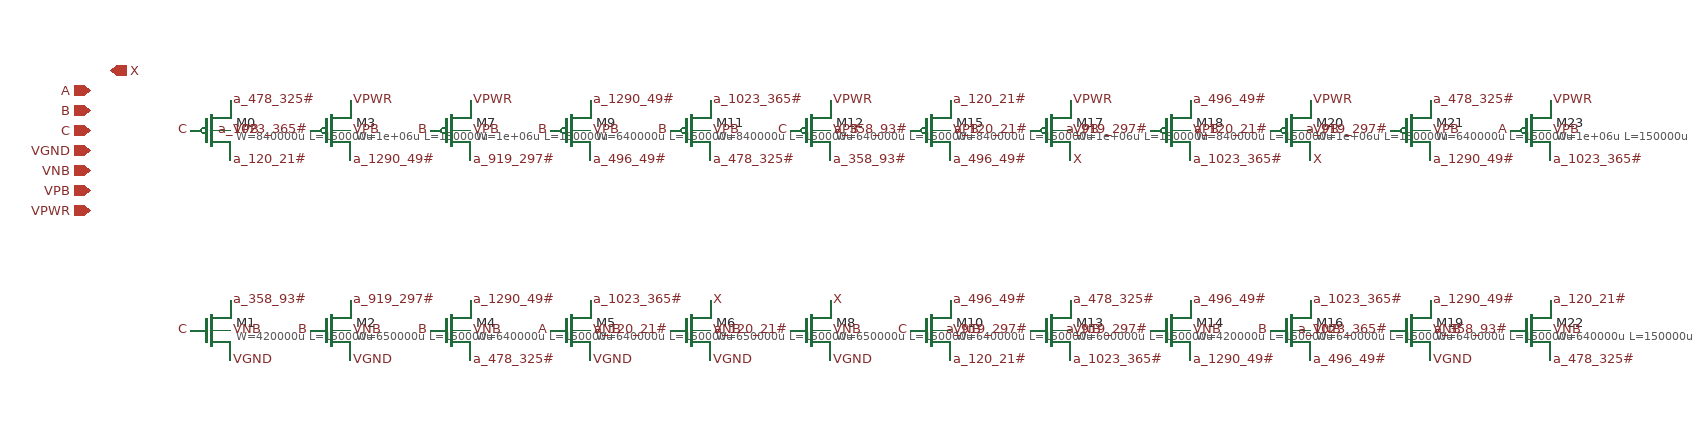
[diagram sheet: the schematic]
v {xschem version=3.4.6RC file_version=1.2
}
G {}
K {}
V {}
S {}
E {}
C {ipin.sym} -120 -40 0 0 {name=p0 lab=A}
C {ipin.sym} -120 -20 0 0 {name=p1 lab=B}
C {ipin.sym} -120 0 0 0 {name=p2 lab=C}
C {ipin.sym} -120 20 0 0 {name=p3 lab=VGND}
C {ipin.sym} -120 40 0 0 {name=p4 lab=VNB}
C {ipin.sym} -120 60 0 0 {name=p5 lab=VPB}
C {ipin.sym} -120 80 0 0 {name=p6 lab=VPWR}
C {opin.sym} -100 -60 0 0 {name=p7 lab=X}
C {sky130_fd_pr/pfet_01v8_hvt.sym} 0 0 0 0 {name=M0
W=840000u
L=150000u
model=pfet_01v8_hvt
spiceprefix=X
}
C {lab_pin.sym} 20 0 2 0 {name=p8 sig_type=std_logic lab=VPB}
C {lab_pin.sym} 20 -30 2 0 {name=p9 sig_type=std_logic lab=a_478_325#}
C {lab_pin.sym} 20 30 2 0 {name=p10 sig_type=std_logic lab=a_120_21#}
C {lab_pin.sym} -20 0 0 0 {name=p11 sig_type=std_logic lab=C}
C {sky130_fd_pr/pfet_01v8_hvt.sym} 120 0 0 0 {name=M3
W=1e+06u
L=150000u
model=pfet_01v8_hvt
spiceprefix=X
}
C {lab_pin.sym} 140 0 2 0 {name=p12 sig_type=std_logic lab=VPB}
C {lab_pin.sym} 140 -30 2 0 {name=p13 sig_type=std_logic lab=VPWR}
C {lab_pin.sym} 140 30 2 0 {name=p14 sig_type=std_logic lab=a_1290_49#}
C {lab_pin.sym} 100 0 0 0 {name=p15 sig_type=std_logic lab=a_1023_365#}
C {sky130_fd_pr/pfet_01v8_hvt.sym} 240 0 0 0 {name=M7
W=1e+06u
L=150000u
model=pfet_01v8_hvt
spiceprefix=X
}
C {lab_pin.sym} 260 0 2 0 {name=p16 sig_type=std_logic lab=VPB}
C {lab_pin.sym} 260 -30 2 0 {name=p17 sig_type=std_logic lab=VPWR}
C {lab_pin.sym} 260 30 2 0 {name=p18 sig_type=std_logic lab=a_919_297#}
C {lab_pin.sym} 220 0 0 0 {name=p19 sig_type=std_logic lab=B}
C {sky130_fd_pr/pfet_01v8_hvt.sym} 360 0 0 0 {name=M9
W=640000u
L=150000u
model=pfet_01v8_hvt
spiceprefix=X
}
C {lab_pin.sym} 380 0 2 0 {name=p20 sig_type=std_logic lab=VPB}
C {lab_pin.sym} 380 -30 2 0 {name=p21 sig_type=std_logic lab=a_1290_49#}
C {lab_pin.sym} 380 30 2 0 {name=p22 sig_type=std_logic lab=a_496_49#}
C {lab_pin.sym} 340 0 0 0 {name=p23 sig_type=std_logic lab=B}
C {sky130_fd_pr/pfet_01v8_hvt.sym} 480 0 0 0 {name=M11
W=840000u
L=150000u
model=pfet_01v8_hvt
spiceprefix=X
}
C {lab_pin.sym} 500 0 2 0 {name=p24 sig_type=std_logic lab=VPB}
C {lab_pin.sym} 500 -30 2 0 {name=p25 sig_type=std_logic lab=a_1023_365#}
C {lab_pin.sym} 500 30 2 0 {name=p26 sig_type=std_logic lab=a_478_325#}
C {lab_pin.sym} 460 0 0 0 {name=p27 sig_type=std_logic lab=B}
C {sky130_fd_pr/pfet_01v8_hvt.sym} 600 0 0 0 {name=M12
W=640000u
L=150000u
model=pfet_01v8_hvt
spiceprefix=X
}
C {lab_pin.sym} 620 0 2 0 {name=p28 sig_type=std_logic lab=VPB}
C {lab_pin.sym} 620 -30 2 0 {name=p29 sig_type=std_logic lab=VPWR}
C {lab_pin.sym} 620 30 2 0 {name=p30 sig_type=std_logic lab=a_358_93#}
C {lab_pin.sym} 580 0 0 0 {name=p31 sig_type=std_logic lab=C}
C {sky130_fd_pr/pfet_01v8_hvt.sym} 720 0 0 0 {name=M15
W=840000u
L=150000u
model=pfet_01v8_hvt
spiceprefix=X
}
C {lab_pin.sym} 740 0 2 0 {name=p32 sig_type=std_logic lab=VPB}
C {lab_pin.sym} 740 -30 2 0 {name=p33 sig_type=std_logic lab=a_120_21#}
C {lab_pin.sym} 740 30 2 0 {name=p34 sig_type=std_logic lab=a_496_49#}
C {lab_pin.sym} 700 0 0 0 {name=p35 sig_type=std_logic lab=a_358_93#}
C {sky130_fd_pr/pfet_01v8_hvt.sym} 840 0 0 0 {name=M17
W=1e+06u
L=150000u
model=pfet_01v8_hvt
spiceprefix=X
}
C {lab_pin.sym} 860 0 2 0 {name=p36 sig_type=std_logic lab=VPB}
C {lab_pin.sym} 860 -30 2 0 {name=p37 sig_type=std_logic lab=VPWR}
C {lab_pin.sym} 860 30 2 0 {name=p38 sig_type=std_logic lab=X}
C {lab_pin.sym} 820 0 0 0 {name=p39 sig_type=std_logic lab=a_120_21#}
C {sky130_fd_pr/pfet_01v8_hvt.sym} 960 0 0 0 {name=M18
W=840000u
L=150000u
model=pfet_01v8_hvt
spiceprefix=X
}
C {lab_pin.sym} 980 0 2 0 {name=p40 sig_type=std_logic lab=VPB}
C {lab_pin.sym} 980 -30 2 0 {name=p41 sig_type=std_logic lab=a_496_49#}
C {lab_pin.sym} 980 30 2 0 {name=p42 sig_type=std_logic lab=a_1023_365#}
C {lab_pin.sym} 940 0 0 0 {name=p43 sig_type=std_logic lab=a_919_297#}
C {sky130_fd_pr/pfet_01v8_hvt.sym} 1080 0 0 0 {name=M20
W=1e+06u
L=150000u
model=pfet_01v8_hvt
spiceprefix=X
}
C {lab_pin.sym} 1100 0 2 0 {name=p44 sig_type=std_logic lab=VPB}
C {lab_pin.sym} 1100 -30 2 0 {name=p45 sig_type=std_logic lab=VPWR}
C {lab_pin.sym} 1100 30 2 0 {name=p46 sig_type=std_logic lab=X}
C {lab_pin.sym} 1060 0 0 0 {name=p47 sig_type=std_logic lab=a_120_21#}
C {sky130_fd_pr/pfet_01v8_hvt.sym} 1200 0 0 0 {name=M21
W=640000u
L=150000u
model=pfet_01v8_hvt
spiceprefix=X
}
C {lab_pin.sym} 1220 0 2 0 {name=p48 sig_type=std_logic lab=VPB}
C {lab_pin.sym} 1220 -30 2 0 {name=p49 sig_type=std_logic lab=a_478_325#}
C {lab_pin.sym} 1220 30 2 0 {name=p50 sig_type=std_logic lab=a_1290_49#}
C {lab_pin.sym} 1180 0 0 0 {name=p51 sig_type=std_logic lab=a_919_297#}
C {sky130_fd_pr/pfet_01v8_hvt.sym} 1320 0 0 0 {name=M23
W=1e+06u
L=150000u
model=pfet_01v8_hvt
spiceprefix=X
}
C {lab_pin.sym} 1340 0 2 0 {name=p52 sig_type=std_logic lab=VPB}
C {lab_pin.sym} 1340 -30 2 0 {name=p53 sig_type=std_logic lab=VPWR}
C {lab_pin.sym} 1340 30 2 0 {name=p54 sig_type=std_logic lab=a_1023_365#}
C {lab_pin.sym} 1300 0 0 0 {name=p55 sig_type=std_logic lab=A}
C {sky130_fd_pr/nfet_01v8.sym} 0 200 0 0 {name=M1
W=420000u
L=150000u
model=nfet_01v8
spiceprefix=X
}
C {lab_pin.sym} 20 200 2 0 {name=p56 sig_type=std_logic lab=VNB}
C {lab_pin.sym} 20 170 2 0 {name=p57 sig_type=std_logic lab=a_358_93#}
C {lab_pin.sym} 20 230 2 0 {name=p58 sig_type=std_logic lab=VGND}
C {lab_pin.sym} -20 200 0 0 {name=p59 sig_type=std_logic lab=C}
C {sky130_fd_pr/nfet_01v8.sym} 120 200 0 0 {name=M2
W=650000u
L=150000u
model=nfet_01v8
spiceprefix=X
}
C {lab_pin.sym} 140 200 2 0 {name=p60 sig_type=std_logic lab=VNB}
C {lab_pin.sym} 140 170 2 0 {name=p61 sig_type=std_logic lab=a_919_297#}
C {lab_pin.sym} 140 230 2 0 {name=p62 sig_type=std_logic lab=VGND}
C {lab_pin.sym} 100 200 0 0 {name=p63 sig_type=std_logic lab=B}
C {sky130_fd_pr/nfet_01v8.sym} 240 200 0 0 {name=M4
W=640000u
L=150000u
model=nfet_01v8
spiceprefix=X
}
C {lab_pin.sym} 260 200 2 0 {name=p64 sig_type=std_logic lab=VNB}
C {lab_pin.sym} 260 170 2 0 {name=p65 sig_type=std_logic lab=a_1290_49#}
C {lab_pin.sym} 260 230 2 0 {name=p66 sig_type=std_logic lab=a_478_325#}
C {lab_pin.sym} 220 200 0 0 {name=p67 sig_type=std_logic lab=B}
C {sky130_fd_pr/nfet_01v8.sym} 360 200 0 0 {name=M5
W=640000u
L=150000u
model=nfet_01v8
spiceprefix=X
}
C {lab_pin.sym} 380 200 2 0 {name=p68 sig_type=std_logic lab=VNB}
C {lab_pin.sym} 380 170 2 0 {name=p69 sig_type=std_logic lab=a_1023_365#}
C {lab_pin.sym} 380 230 2 0 {name=p70 sig_type=std_logic lab=VGND}
C {lab_pin.sym} 340 200 0 0 {name=p71 sig_type=std_logic lab=A}
C {sky130_fd_pr/nfet_01v8.sym} 480 200 0 0 {name=M6
W=650000u
L=150000u
model=nfet_01v8
spiceprefix=X
}
C {lab_pin.sym} 500 200 2 0 {name=p72 sig_type=std_logic lab=VNB}
C {lab_pin.sym} 500 170 2 0 {name=p73 sig_type=std_logic lab=X}
C {lab_pin.sym} 500 230 2 0 {name=p74 sig_type=std_logic lab=VGND}
C {lab_pin.sym} 460 200 0 0 {name=p75 sig_type=std_logic lab=a_120_21#}
C {sky130_fd_pr/nfet_01v8.sym} 600 200 0 0 {name=M8
W=650000u
L=150000u
model=nfet_01v8
spiceprefix=X
}
C {lab_pin.sym} 620 200 2 0 {name=p76 sig_type=std_logic lab=VNB}
C {lab_pin.sym} 620 170 2 0 {name=p77 sig_type=std_logic lab=X}
C {lab_pin.sym} 620 230 2 0 {name=p78 sig_type=std_logic lab=VGND}
C {lab_pin.sym} 580 200 0 0 {name=p79 sig_type=std_logic lab=a_120_21#}
C {sky130_fd_pr/nfet_01v8.sym} 720 200 0 0 {name=M10
W=640000u
L=150000u
model=nfet_01v8
spiceprefix=X
}
C {lab_pin.sym} 740 200 2 0 {name=p80 sig_type=std_logic lab=VNB}
C {lab_pin.sym} 740 170 2 0 {name=p81 sig_type=std_logic lab=a_496_49#}
C {lab_pin.sym} 740 230 2 0 {name=p82 sig_type=std_logic lab=a_120_21#}
C {lab_pin.sym} 700 200 0 0 {name=p83 sig_type=std_logic lab=C}
C {sky130_fd_pr/nfet_01v8.sym} 840 200 0 0 {name=M13
W=600000u
L=150000u
model=nfet_01v8
spiceprefix=X
}
C {lab_pin.sym} 860 200 2 0 {name=p84 sig_type=std_logic lab=VNB}
C {lab_pin.sym} 860 170 2 0 {name=p85 sig_type=std_logic lab=a_478_325#}
C {lab_pin.sym} 860 230 2 0 {name=p86 sig_type=std_logic lab=a_1023_365#}
C {lab_pin.sym} 820 200 0 0 {name=p87 sig_type=std_logic lab=a_919_297#}
C {sky130_fd_pr/nfet_01v8.sym} 960 200 0 0 {name=M14
W=420000u
L=150000u
model=nfet_01v8
spiceprefix=X
}
C {lab_pin.sym} 980 200 2 0 {name=p88 sig_type=std_logic lab=VNB}
C {lab_pin.sym} 980 170 2 0 {name=p89 sig_type=std_logic lab=a_496_49#}
C {lab_pin.sym} 980 230 2 0 {name=p90 sig_type=std_logic lab=a_1290_49#}
C {lab_pin.sym} 940 200 0 0 {name=p91 sig_type=std_logic lab=a_919_297#}
C {sky130_fd_pr/nfet_01v8.sym} 1080 200 0 0 {name=M16
W=640000u
L=150000u
model=nfet_01v8
spiceprefix=X
}
C {lab_pin.sym} 1100 200 2 0 {name=p92 sig_type=std_logic lab=VNB}
C {lab_pin.sym} 1100 170 2 0 {name=p93 sig_type=std_logic lab=a_1023_365#}
C {lab_pin.sym} 1100 230 2 0 {name=p94 sig_type=std_logic lab=a_496_49#}
C {lab_pin.sym} 1060 200 0 0 {name=p95 sig_type=std_logic lab=B}
C {sky130_fd_pr/nfet_01v8.sym} 1200 200 0 0 {name=M19
W=640000u
L=150000u
model=nfet_01v8
spiceprefix=X
}
C {lab_pin.sym} 1220 200 2 0 {name=p96 sig_type=std_logic lab=VNB}
C {lab_pin.sym} 1220 170 2 0 {name=p97 sig_type=std_logic lab=a_1290_49#}
C {lab_pin.sym} 1220 230 2 0 {name=p98 sig_type=std_logic lab=VGND}
C {lab_pin.sym} 1180 200 0 0 {name=p99 sig_type=std_logic lab=a_1023_365#}
C {sky130_fd_pr/nfet_01v8.sym} 1320 200 0 0 {name=M22
W=640000u
L=150000u
model=nfet_01v8
spiceprefix=X
}
C {lab_pin.sym} 1340 200 2 0 {name=p100 sig_type=std_logic lab=VNB}
C {lab_pin.sym} 1340 170 2 0 {name=p101 sig_type=std_logic lab=a_120_21#}
C {lab_pin.sym} 1340 230 2 0 {name=p102 sig_type=std_logic lab=a_478_325#}
C {lab_pin.sym} 1300 200 0 0 {name=p103 sig_type=std_logic lab=a_358_93#}
